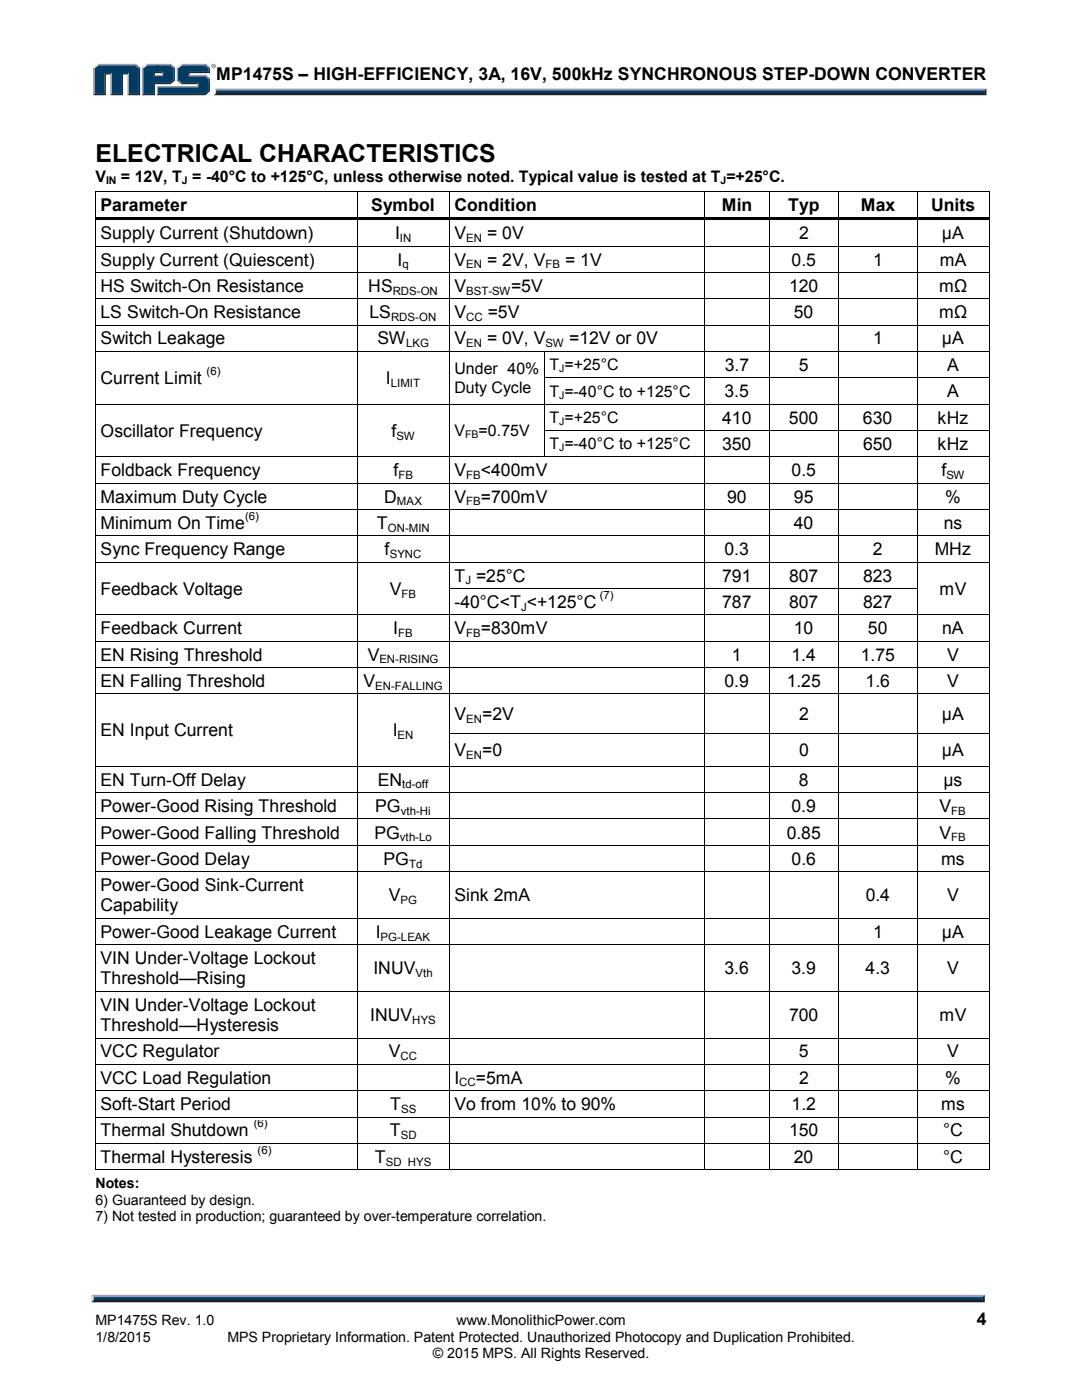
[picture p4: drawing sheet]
<svg xmlns="http://www.w3.org/2000/svg" width="216mm" height="279mm" viewBox="0 0 216 279" stroke-linecap="round" stroke-linejoin="round" font-family="sans-serif">
<defs><g id="words">
<text font-size="5" x="19" y="32.4">ELECTRICAL CHARACTERISTICS</text>
<g font-size="3.5">
<text x="43.1" y="15.9">MP1475S – HIGH-EFFICIENCY, 3A, 16V, 500kHz SYNCHRONOUS STEP-DOWN CONVERTER</text>
<text x="20.1" y="42.1">Parameter</text>
<text x="20.1" y="47.8">Supply Current (Shutdown)</text>
<text x="74.1" y="42.1">Symbol</text>
<text x="78.8" y="47.8">I</text>
<text x="90.7" y="42.1">Condition</text>
<text x="90.7" y="47.8">V</text>
<text x="97.2" y="47.8">= 0V</text>
<text x="144" y="42.1">Min</text>
<text x="157.3" y="42.1">Typ</text>
<text x="159.4" y="47.8">2</text>
<text x="171.8" y="42.1">Max</text>
<text x="185.8" y="42.1">Units</text>
<text x="188" y="47.8">μA</text>
<text x="20.1" y="53">Supply Current (Quiescent)</text>
<text x="79.3" y="53">I</text>
<text x="90.7" y="53">V</text>
<text x="97.2" y="53">= 2V, V</text>
<text x="112.8" y="53">= 1V</text>
<text x="158" y="53">0.5</text>
<text x="174.2" y="53">1</text>
<text x="187.5" y="53">mA</text>
<text x="20.1" y="58.3">HS Switch-On Resistance</text>
<text x="73.5" y="58.3">HS</text>
<text x="90.7" y="58.3">V</text>
<text x="102" y="58.3">=5V</text>
<text x="157.4" y="58.3">120</text>
<text x="187.4" y="58.3">mΩ</text>
<text x="20.1" y="63.5">LS Switch-On Resistance</text>
<text x="73.7" y="63.5">LS</text>
<text x="90.7" y="63.5">V</text>
<text x="97.3" y="63.5">=5V</text>
<text x="158.4" y="63.5">50</text>
<text x="187.4" y="63.5">mΩ</text>
<text x="20.1" y="68.7">Switch Leakage</text>
<text x="75.3" y="68.7">SW</text>
<text x="90.7" y="68.7">V</text>
<text x="97.2" y="68.7">= 0V, V</text>
<text x="113.6" y="68.7">=12V or 0V</text>
<text x="174.2" y="68.7">1</text>
<text x="188" y="68.7">μA</text>
<text x="20.1" y="76.7">Current Limit</text>
<text x="77" y="76.7">I</text>
<text x="144.6" y="74">3.7</text>
<text x="159.4" y="74">5</text>
<text x="189" y="74">A</text>
<text x="144.6" y="79.3">3.5</text>
<text x="189" y="79.3">A</text>
<text x="20.1" y="87.2">Oscillator Frequency</text>
<text x="78.1" y="87.2">f</text>
<text x="144.1" y="84.5">410</text>
<text x="144.1" y="89.8">350</text>
<text x="157.4" y="84.5">500</text>
<text x="172.2" y="84.5">630</text>
<text x="172.2" y="89.8">650</text>
<text x="187.1" y="84.5">kHz</text>
<text x="187.1" y="89.8">kHz</text>
<text x="20.1" y="95">Foldback Frequency</text>
<text x="78.5" y="95">f</text>
<text x="90.7" y="95">V</text>
<text x="95.9" y="95">&lt;400mV</text>
<text x="158" y="95">0.5</text>
<text x="187.8" y="95">f</text>
<text x="20.1" y="100.3">Maximum Duty Cycle</text>
<text x="76.7" y="100.3">D</text>
<text x="90.7" y="100.3">V</text>
<text x="95.9" y="100.3">=700mV</text>
<text x="145.1" y="100.3">90</text>
<text x="158.4" y="100.3">95</text>
<text x="188.6" y="100.3">%</text>
<text x="20.1" y="105.6">Minimum On Time</text>
<text x="75.2" y="105.6">T</text>
<text x="158.4" y="105.6">40</text>
<text x="188.3" y="105.6">ns</text>
<text x="20.1" y="110.8">Sync Frequency Range</text>
<text x="76.7" y="110.8">f</text>
<text x="144.6" y="110.8">0.3</text>
<text x="174.2" y="110.8">2</text>
<text x="186.5" y="110.8">MHz</text>
<text x="20.1" y="118.7">Feedback Voltage</text>
<text x="77.8" y="118.7">V</text>
<text x="90.7" y="116.1">T =25°C</text>
<text x="144.1" y="116.1">791</text>
<text x="157.4" y="116.1">807</text>
<text x="172.2" y="116.1">823</text>
<text x="187.5" y="118.7">mV</text>
<text x="90.7" y="121.3">-40°C&lt;T &lt;+125°C</text>
<text x="144.1" y="121.3">787</text>
<text x="157.4" y="121.3">807</text>
<text x="172.2" y="121.3">827</text>
<text x="20.1" y="126.6">Feedback Current</text>
<text x="20.1" y="131.8">EN Rising Threshold</text>
<text x="73.4" y="131.8">V</text>
<text x="78.5" y="126.6">I</text>
<text x="90.7" y="126.6">V</text>
<text x="95.9" y="126.6">=830mV</text>
<text x="146.1" y="131.8">1</text>
<text x="157.9" y="131.8">1.4</text>
<text x="158.4" y="126.6">10</text>
<text x="171.7" y="131.8">1.75</text>
<text x="173.2" y="126.6">50</text>
<text x="188" y="126.6">nA</text>
<text x="189" y="131.8">V</text>
<text x="20.1" y="137.1">EN Falling Threshold</text>
<text x="72.5" y="137.1">V</text>
<text x="144.6" y="137.1">0.9</text>
<text x="157" y="137.1">1.25</text>
<text x="172.7" y="137.1">1.6</text>
<text x="189" y="137.1">V</text>
<text x="90.7" y="143.7">V</text>
<text x="96.2" y="143.7">=2V</text>
<text x="159.4" y="143.7">2</text>
<text x="188" y="143.7">μA</text>
<text x="20.1" y="146.9">EN Input Current</text>
<text x="78.4" y="146.9">I</text>
<text x="90.7" y="150.9">V</text>
<text x="96.2" y="150.9">=0</text>
<text x="159.4" y="150.9">0</text>
<text x="188" y="150.9">μA</text>
<text x="20.1" y="156.8">EN Turn-Off Delay</text>
<text x="75.4" y="156.8">EN</text>
<text x="159.4" y="156.8">8</text>
<text x="188.3" y="156.8">μs</text>
<text x="20.1" y="162.1">Power-Good Rising Threshold</text>
<text x="20.1" y="167.3">Power-Good Falling Threshold</text>
<text x="74.7" y="167.3">PG</text>
<text x="74.9" y="162.1">PG</text>
<text x="157" y="167.3">0.85</text>
<text x="157.9" y="162.1">0.9</text>
<text x="187.5" y="167.3">V</text>
<text x="187.5" y="162.1">V</text>
<text x="20.1" y="172.6">Power-Good Delay</text>
<text x="76.5" y="172.6">PG</text>
<text x="157.9" y="172.6">0.6</text>
<text x="187.8" y="172.6">ms</text>
<text x="20.1" y="177.8">Power-Good Sink-Current</text>
<text x="77.6" y="179.9">V</text>
<text x="90.7" y="179.9">Sink 2mA</text>
<text x="172.7" y="179.9">0.4</text>
<text x="189" y="179.9">V</text>
<text x="20.1" y="181.9">Capability</text>
<text x="20.1" y="187.2">Power-Good Leakage Current</text>
<text x="75" y="187.2">I</text>
<text x="174.2" y="187.2">1</text>
<text x="188" y="187.2">μA</text>
<text x="20.1" y="192.4">VIN Under-Voltage Lockout</text>
<text x="20.1" y="196.5">Threshold—Rising</text>
<text x="74.5" y="194.4">INUV</text>
<text x="144.6" y="194.4">3.6</text>
<text x="157.9" y="194.4">3.9</text>
<text x="172.7" y="194.4">4.3</text>
<text x="189" y="194.4">V</text>
<text x="20.1" y="201.7">VIN Under-Voltage Lockout</text>
<text x="73.9" y="203.8">INUV</text>
<text x="157.4" y="203.8">700</text>
<text x="187.5" y="203.8">mV</text>
<text x="20.1" y="205.8">Threshold—Hysteresis</text>
<text x="20.1" y="211">VCC Regulator</text>
<text x="77.6" y="211">V</text>
<text x="159.4" y="211">5</text>
<text x="189" y="211">V</text>
<text x="20.1" y="216.3">VCC Load Regulation</text>
<text x="20.1" y="221.5">Soft-Start Period</text>
<text x="77.8" y="221.5">T</text>
<text x="90.7" y="216.3">I</text>
<text x="90.7" y="221.5">Vo from 10% to 90%</text>
<text x="95" y="216.3">=5mA</text>
<text x="158" y="221.5">1.2</text>
<text x="159.4" y="216.3">2</text>
<text x="187.8" y="221.5">ms</text>
<text x="188.6" y="216.3">%</text>
<text x="20.1" y="226.8">Thermal Shutdown</text>
<text x="77.8" y="226.8">T</text>
<text x="157.4" y="226.8">150</text>
<text x="188.2" y="226.8">°C</text>
<text x="20.1" y="232.1">Thermal Hysteresis</text>
<text x="74.8" y="232.1">T</text>
<text x="158.4" y="232.1">20</text>
<text x="188.2" y="232.1">°C</text>
<text x="194.9" y="264.5">4</text>
</g>
<g font-size="3.2">
<text x="19" y="36.4">V</text>
<text x="24.1" y="36.4">= 12V, T = -40°C to +125°C, unless otherwise noted. Typical value is tested at T =+25°C.</text>
<text x="90.7" y="74.7">Under 40%</text>
<text x="109.6" y="73.9">T =+25°C</text>
<text x="90.7" y="78.4">Duty Cycle</text>
<text x="109.6" y="79.2">T =-40°C to +125°C</text>
<text x="90.7" y="87.1">V</text>
<text x="95.5" y="87.1">=0.75V</text>
<text x="109.6" y="84.5">T =+25°C</text>
<text x="109.6" y="89.7">T =-40°C to +125°C</text>
</g>
<g font-size="2.8">
<text x="19" y="237.2">Notes:</text>
<text x="19" y="240.4">6) Guaranteed by design.</text>
<text x="19" y="243.7">7) Not tested in production; guaranteed by over-temperature correlation.</text>
<text x="19" y="267.9">1/8/2015</text>
<text x="19" y="264.5">MP1475S Rev. 1.0</text>
<text x="45.4" y="267.9">MPS Proprietary Information. Patent Protected. Unauthorized Photocopy and Duplication Prohibited.</text>
<text x="91.1" y="264.5">www.MonolithicPower.com</text>
<text x="86.4" y="271.1">© 2015 MPS. All Rights Reserved.</text>
</g>
<g font-size="2.3">
<text x="79.8" y="48.3">IN</text>
<text x="80.3" y="53.6">q</text>
<text x="93" y="48.3">EN</text>
<text x="93" y="53.6">EN</text>
<text x="108.8" y="53.6">FB</text>
<text x="78.4" y="58.8">RDS-ON</text>
<text x="93" y="58.8">BST-SW</text>
<text x="78" y="64.1">RDS-ON</text>
<text x="93" y="64.1">CC</text>
<text x="81" y="69.3">LKG</text>
<text x="93" y="69.3">EN</text>
<text x="108.8" y="69.3">SW</text>
<text x="41.2" y="74.9">(6)</text>
<text x="78" y="77.2">LIMIT</text>
<text x="79.1" y="87.7">SW</text>
<text x="79.5" y="95.6">FB</text>
<text x="93" y="95.6">FB</text>
<text x="188.8" y="95.6">SW</text>
<text x="79.2" y="100.8">MAX</text>
<text x="93" y="100.8">FB</text>
<text x="48.9" y="103.8">(6)</text>
<text x="77.4" y="106.1">ON-MIN</text>
<text x="77.8" y="111.4">SYNC</text>
<text x="80.1" y="119.3">FB</text>
<text x="92.9" y="116.6">J</text>
<text x="119.7" y="119.5">(7)</text>
<text x="104" y="121.9">J</text>
<text x="79.5" y="127.1">FB</text>
<text x="93" y="127.1">FB</text>
<text x="74.8" y="137.6">EN-FALLING</text>
<text x="75.7" y="132.4">EN-RISING</text>
<text x="79.3" y="147.5">EN</text>
<text x="93" y="144.2">EN</text>
<text x="93" y="151.4">EN</text>
<text x="80.3" y="157.4">td-off</text>
<text x="79.8" y="167.9">vth-Lo</text>
<text x="80" y="162.6">vth-Hi</text>
<text x="189.8" y="162.6">FB</text>
<text x="189.8" y="167.9">FB</text>
<text x="81.6" y="173.1">Td</text>
<text x="79.9" y="180.4">PG</text>
<text x="75.9" y="187.7">PG-LEAK</text>
<text x="82.9" y="195">Vth</text>
<text x="82.3" y="204.3">HYS</text>
<text x="79.9" y="211.6">CC</text>
<text x="91.7" y="216.8">CC</text>
<text x="50.6" y="225">(6)</text>
<text x="80" y="227.3">SD</text>
<text x="80.1" y="222.1">SS</text>
<text x="51.4" y="230.3">(6)</text>
<text x="77" y="232.6">SD HYS</text>
</g>
<g font-size="2.1">
<text x="21.2" y="36.7">IN</text>
<text x="36.3" y="36.7">J</text>
<text x="143.8" y="36.7">J</text>
<text x="111.5" y="74.3">J</text>
<text x="111.5" y="79.5">J</text>
<text x="92.8" y="87.4">FB</text>
<text x="111.5" y="84.8">J</text>
<text x="111.5" y="90">J</text>
</g>
</g></defs>
<path d="M18.7 259.2h177.4l.4 .7h-178.3z" fill="#231f20"/>
<path d="M18.3 258.4h178.2l-.4 .8h-177.4z" fill="#94a0b9"/>
<path d="M196.5 258.4v1.5l-.4-.4v-.6z" fill="#001339"/>
<path d="M18.7 258.9h177.4v.6h-177.4z" fill="#003b63"/>
<path d="M18.2 258.4l.5 .5v.5l-.5 .5z" fill="#dcddde"/>
<path d="M42.9 17.7h153.9l-.4 .7h-153.3z" fill="#94a0b9"/>
<path d="M43.1 18.4h153.3l.4 .6h-154.3l.4-.2z" fill="#231f20"/>
<path d="M196.4 18.1l.4-.4v1.3l-.4-.4z" fill="#001339"/>
<path d="M43.1 18.1h153.3v.5h-153.4z" fill="#003b63"/>
<path d="M42.9 17.7l.2 .5a.79 .79 0 0 1-.6 .8l.1-.1a1.23 1.23 0 0 0 .3-1.2z" fill="#dcddde"/>
<path d="M30.7 15.2l.2-.3h1.4l.3 .3z" fill="#94a0b9"/>
<g fill="#003b63">
<path d="M18.9 13.6l.8-.6h7.2l.8 .6v5.1h-2v-4.1h-1.4v4.1h-2v-4.1h-1.5v4.1h-1.9z"/>
<path d="M28.6 13.6l.8-.6h2.2v1.3h-.9v.9h1.9v-.9h-1.3v-1.3h2.5l.8 .6v2.3l-.8 .6h-3.1v2.2h-2.1z"/>
<path d="M31.5 17.4h8v-.9h-3.2l-.8-.6v-2.3l.8-.6h4.5l.8 .6v.7h-4v.9h3.2l.8 .6v2.2l-.8 .7h-9.3z"/>
</g>
<path d="M36.2 12.9h4.8" fill="none" stroke="#94a0b9" stroke-width=".26"/>
<path d="M35.3 13.4l.9-.7 .1 .3-.8 .6z" fill="#dcddde"/>
<path d="M35.4 13.4v2.7" fill="none" stroke="#94a0b9" stroke-width=".27"/>
<path d="M35.3 16.1l.2-.2 .8 .6-.1 .3z" fill="#547194"/>
<path d="M36.2 16.7h3.4" fill="none" stroke="#001339" stroke-width=".26"/>
<g fill="#94a0b9">
<path d="M31.3 17.2h8v-.4l.3-.3v.9h-8z"/>
<path d="M31.3 17.2l.3 .2v1.3l-.3 .3z"/>
</g>
<path d="M37.6 14.3h4v-.7l.3-.2v1.2h-4.1v.3l-.2 .3z" fill="#001339"/>
<path d="M37.6 15.1h3.4" fill="none" stroke="#94a0b9" stroke-width=".26"/>
<path d="M41 14.9l.9 .8-.3 .1-.8-.6z" fill="#547194"/>
<g fill="#001339">
<path d="M31.3 19l.3-.3h9.2l.8-.7v-2.2l.3-.1v2.5l-.9 .8z"/>
<path d="M30.7 16.5h3.1l.8-.6v-2.3l.3-.2v2.7l-.9 .7h-3.1v2.2h-2.6l.3-.3h2.1z"/>
</g>
<path d="M34 12.7l.9 .7-.3 .2-.8-.6z" fill="#547194"/>
<path d="M29.2 12.9h4.8" fill="none" stroke="#94a0b9" stroke-width=".26"/>
<path d="M28.3 13.4l.9-.7 .2 .3-.8 .6z" fill="#dcddde"/>
<path d="M28.5 13.4v5.6" fill="none" stroke="#94a0b9" stroke-width=".27"/>
<path d="M32.3 14.6l.3-.3v.9l-.3-.3z" fill="#94a0b9"/>
<g fill="#001339">
<path d="M30.7 14.3h1.9l-.3 .3h-1.4v.3l-.2 .3z"/>
<path d="M27.7 13.6l.3-.2v5.6h-2.6l.3-.3h2z"/>
</g>
<path d="M27.1 12.7l.9 .7-.3 .2-.8-.6z" fill="#547194"/>
<path d="M19.5 12.9h7.6" fill="none" stroke="#94a0b9" stroke-width=".26"/>
<path d="M18.6 13.4l.9-.7 .2 .3-.8 .6z" fill="#dcddde"/>
<path d="M18.7 13.4v5.6" fill="none" stroke="#94a0b9" stroke-width=".27"/>
<path d="M20.8 14.6h1.5l-.3 .3h-.9v4.1h-2.5l.3-.3h1.9z" fill="#001339"/>
<path d="M22.1 14.6v4.4" fill="none" stroke="#94a0b9" stroke-width=".27"/>
<path d="M24.3 14.6h1.4l-.3 .3h-.9v4.1h-2.5l.3-.3h2z" fill="#001339"/>
<path d="M25.6 14.6v4.4" fill="none" stroke="#94a0b9" stroke-width=".27"/>
<path d="M41 12.7l.9 .7-.3 .2-.8-.6z" fill="#547194"/>
<path d="M42.2 13.2a.45 .45 0 0 1 .9 0 .45 .45 0 0 1-.9 0zM42.3 13.2a.37 .37 0 0 0 .7 0 .37 .37 0 0 0-.7 0zM42.5 12.9l.3 .1v.4l-.2-.2-.1 .2zM42.5 13v.2l.2-.1z" fill="#231f20"/>
<g fill="#000">
<path d="M19 38.2h.1v.7h-.1zM71.2 38.2h.2v.7h-.2zM89.6 38.2h.1v.7h-.1zM140.5 38.2h.2v.7h-.2zM153.4 38.2h.2v.7h-.2zM167.3 38.2h.1v.7h-.1zM182.9 38.2h.2v.7h-.2zM197.3 38.2h.1v.7h-.1zM197.3 38.2h.1v.2h-.1zM19 43.4h.1v1.1h-.1zM19 49.1h.1v.6h-.1zM19 54.3h.1v.7h-.1z"/>
<path d="M19.1 43.4h52.1v.5h-52.1zM71.2 43.9h.2v.6h-.2zM71.2 43.4h18.4v.5h-18.4zM71.2 49.1h.2v.6h-.2zM71.2 54.3h.2v.7h-.2zM89.6 43.9h.1v.6h-.1zM89.6 43.4h50.9v.5h-50.9zM89.6 49.1h.1v.6h-.1zM89.6 54.3h.1v.7h-.1zM140.5 43.9h.2v.6h-.2zM140.5 43.4h12.9v.5h-12.9zM140.5 49.1h.2v.6h-.2z"/>
<path d="M140.5 54.3h.2v.7h-.2zM153.4 43.9h.2v.6h-.2zM153.4 43.4h13.9v.5h-13.9zM153.4 49.1h.2v.6h-.2zM153.4 54.3h.2v.7h-.2zM167.3 43.9h.1v.6h-.1zM167.3 43.4h15.6v.5h-15.6zM167.3 49.1h.1v.6h-.1zM167.3 54.3h.1v.7h-.1zM182.9 43.9h.2v.6h-.2zM182.9 43.4h14.4v.5h-14.4zM182.9 49.1h.2v.6h-.2z"/>
<path d="M182.9 54.3h.2v.7h-.2zM197.3 43.4h.1v1.1h-.1zM197.3 49.1h.1v.6h-.1zM197.3 54.3h.1v.7h-.1zM19 59.6h.1v.6h-.1zM19 64.8h.1v.7h-.1zM19 70.1h.1v.6h-.1zM19 75.3h.1v.7h-.1zM71.2 59.6h.2v.6h-.2zM71.2 64.8h.2v.7h-.2zM71.2 70.1h.2v.6h-.2zM71.2 75.3h.2v.7h-.2z"/>
<path d="M89.6 59.6h.1v.6h-.1zM89.6 64.8h.1v.7h-.1zM89.6 70.1h.1v.6h-.1zM89.6 75.3h.1v.7h-.1zM108.5 70.1h.2v.6h-.2zM108.5 75.3h.2v.7h-.2zM140.5 59.6h.2v.6h-.2zM140.5 64.8h.2v.7h-.2zM140.5 70.1h.2v.6h-.2zM140.5 75.3h.2v.7h-.2zM153.4 59.6h.2v.6h-.2zM153.4 64.8h.2v.7h-.2z"/>
<path d="M153.4 70.1h.2v.6h-.2zM153.4 75.3h.2v.7h-.2zM167.3 59.6h.1v.6h-.1zM167.3 64.8h.1v.7h-.1zM167.3 70.1h.1v.6h-.1zM167.3 75.3h.1v.7h-.1zM182.9 59.6h.2v.6h-.2zM182.9 64.8h.2v.7h-.2zM182.9 70.1h.2v.6h-.2zM182.9 75.3h.2v.7h-.2zM197.3 59.6h.1v.6h-.1zM197.3 64.8h.1v.7h-.1z"/>
<path d="M197.3 70.1h.1v.6h-.1zM197.3 75.3h.1v.7h-.1zM19 80.6h.1v.7h-.1zM19 85.9h.1v.6h-.1zM19 91.1h.1v.7h-.1zM19 96.4h.1v.6h-.1zM71.2 80.6h.2v.7h-.2zM71.2 85.9h.2v.6h-.2zM71.2 91.1h.2v.7h-.2zM71.2 96.4h.2v.6h-.2zM89.6 80.6h.1v.7h-.1zM89.6 85.9h.1v.6h-.1z"/>
<path d="M89.6 91.1h.1v.7h-.1zM89.6 96.4h.1v.6h-.1zM108.5 80.6h.2v.7h-.2zM108.5 85.9h.2v.6h-.2zM140.5 80.6h.2v.7h-.2zM140.5 85.9h.2v.6h-.2zM140.5 91.1h.2v.7h-.2zM140.5 96.4h.2v.6h-.2zM153.4 80.6h.2v.7h-.2zM153.4 85.9h.2v.6h-.2zM153.4 91.1h.2v.7h-.2zM153.4 96.4h.2v.6h-.2z"/>
<path d="M167.3 80.6h.1v.7h-.1zM167.3 85.9h.1v.6h-.1zM167.3 91.1h.1v.7h-.1zM167.3 96.4h.1v.6h-.1zM182.9 80.6h.2v.7h-.2zM182.9 85.9h.2v.6h-.2zM182.9 91.1h.2v.7h-.2zM182.9 96.4h.2v.6h-.2zM197.3 80.6h.1v.7h-.1zM197.3 85.9h.1v.6h-.1zM197.3 91.1h.1v.7h-.1zM197.3 96.4h.1v.6h-.1z"/>
<path d="M19 101.6h.1v.7h-.1zM19 106.8h.1v.7h-.1zM19 112.1h.1v.7h-.1zM19 117.4h.1v.7h-.1zM71.2 101.6h.2v.7h-.2zM71.2 106.8h.2v.7h-.2zM71.2 112.1h.2v.7h-.2zM71.2 117.4h.2v.7h-.2zM89.6 101.6h.1v.7h-.1zM89.6 106.8h.1v.7h-.1zM89.6 112.1h.1v.7h-.1zM89.6 117.4h.1v.7h-.1z"/>
<path d="M140.5 101.6h.2v.7h-.2zM140.5 106.8h.2v.7h-.2zM140.5 112.1h.2v.7h-.2zM140.5 117.4h.2v.7h-.2zM153.4 101.6h.2v.7h-.2zM153.4 106.8h.2v.7h-.2zM153.4 112.1h.2v.7h-.2zM153.4 117.4h.2v.7h-.2zM167.3 101.6h.1v.7h-.1zM167.3 106.8h.1v.7h-.1zM167.3 112.1h.1v.7h-.1zM167.3 117.4h.1v.7h-.1z"/>
<path d="M182.9 101.6h.2v.7h-.2zM182.9 106.8h.2v.7h-.2zM182.9 112.1h.2v.7h-.2zM182.9 117.4h.2v.7h-.2zM197.3 101.6h.1v.7h-.1zM197.3 106.8h.1v.7h-.1zM197.3 112.1h.1v.7h-.1zM197.3 117.4h.1v.7h-.1zM19 122.6h.1v.7h-.1zM19 127.9h.1v.7h-.1zM19 133.1h.1v.7h-.1zM19 138.4h.1v.7h-.1z"/>
<path d="M71.2 122.6h.2v.7h-.2zM71.2 127.9h.2v.7h-.2zM71.2 133.1h.2v.7h-.2zM71.2 138.4h.2v.7h-.2zM89.6 122.6h.1v.7h-.1zM89.6 127.9h.1v.7h-.1zM89.6 133.1h.1v.7h-.1zM89.6 138.4h.1v.7h-.1zM140.5 122.6h.2v.7h-.2zM140.5 127.9h.2v.7h-.2zM140.5 133.1h.2v.7h-.2zM140.5 138.4h.2v.7h-.2z"/>
<path d="M153.4 122.6h.2v.7h-.2zM153.4 127.9h.2v.7h-.2zM153.4 133.1h.2v.7h-.2zM153.4 138.4h.2v.7h-.2zM167.3 122.6h.1v.7h-.1zM167.3 127.9h.1v.7h-.1zM167.3 133.1h.1v.7h-.1zM167.3 138.4h.1v.7h-.1zM182.9 122.6h.2v.7h-.2zM182.9 127.9h.2v.7h-.2zM182.9 133.1h.2v.7h-.2zM182.9 138.4h.2v.7h-.2z"/>
<path d="M197.3 122.6h.1v.7h-.1zM197.3 127.9h.1v.7h-.1zM197.3 133.1h.1v.7h-.1zM197.3 138.4h.1v.7h-.1zM19 146.3h.1v.7h-.1zM19 152.9h.1v.6h-.1zM19 158.1h.1v.7h-.1zM71.2 146.3h.2v.7h-.2zM71.2 152.9h.2v.6h-.2zM71.2 158.1h.2v.7h-.2zM89.6 146.3h.1v.7h-.1zM89.6 152.9h.1v.6h-.1z"/>
<path d="M89.6 158.1h.1v.7h-.1zM140.5 146.3h.2v.7h-.2zM140.5 152.9h.2v.6h-.2zM140.5 158.1h.2v.7h-.2zM153.4 146.3h.2v.7h-.2zM153.4 152.9h.2v.6h-.2zM153.4 158.1h.2v.7h-.2zM167.3 146.3h.1v.7h-.1zM167.3 152.9h.1v.6h-.1zM167.3 158.1h.1v.7h-.1zM182.9 146.3h.2v.7h-.2zM182.9 152.9h.2v.6h-.2z"/>
<path d="M182.9 158.1h.2v.7h-.2zM197.3 146.3h.1v.7h-.1zM197.3 152.9h.1v.6h-.1zM197.3 158.1h.1v.7h-.1zM19 163.4h.1v.6h-.1zM19 168.7h.1v.6h-.1zM19 173.9h.1v.7h-.1zM71.2 163.4h.2v.6h-.2zM71.2 168.7h.2v.6h-.2zM71.2 173.9h.2v.7h-.2zM89.6 163.4h.1v.6h-.1zM89.6 168.7h.1v.6h-.1z"/>
<path d="M89.6 173.9h.1v.7h-.1zM140.5 163.4h.2v.6h-.2zM140.5 168.7h.2v.6h-.2zM140.5 173.9h.2v.7h-.2zM153.4 163.4h.2v.6h-.2zM153.4 168.7h.2v.6h-.2zM153.4 173.9h.2v.7h-.2zM167.3 163.4h.1v.6h-.1zM167.3 168.7h.1v.6h-.1zM167.3 173.9h.1v.7h-.1zM182.9 163.4h.2v.6h-.2zM182.9 168.7h.2v.6h-.2z"/>
<path d="M182.9 173.9h.2v.7h-.2zM197.3 163.4h.1v.6h-.1zM197.3 168.7h.1v.6h-.1zM197.3 173.9h.1v.7h-.1zM19 183.2h.1v.7h-.1zM19 188.5h.1v.6h-.1zM19 197.8h.1v.7h-.1zM71.2 183.2h.2v.7h-.2zM71.2 188.5h.2v.6h-.2zM71.2 197.8h.2v.7h-.2zM89.6 183.2h.1v.7h-.1zM89.6 188.5h.1v.6h-.1z"/>
<path d="M89.6 197.8h.1v.7h-.1zM140.5 183.2h.2v.7h-.2zM140.5 188.5h.2v.6h-.2zM140.5 197.8h.2v.7h-.2zM153.4 183.2h.2v.7h-.2zM153.4 188.5h.2v.6h-.2zM153.4 197.8h.2v.7h-.2zM167.3 183.2h.1v.7h-.1zM167.3 188.5h.1v.6h-.1zM167.3 197.8h.1v.7h-.1zM182.9 183.2h.2v.7h-.2zM182.9 188.5h.2v.6h-.2z"/>
<path d="M182.9 197.8h.2v.7h-.2zM197.3 183.2h.1v.7h-.1zM197.3 188.5h.1v.6h-.1zM197.3 197.8h.1v.7h-.1zM19 207.1h.1v.7h-.1zM19 212.3h.1v.7h-.1zM19 217.6h.1v.7h-.1zM71.2 207.1h.2v.7h-.2zM71.2 212.3h.2v.7h-.2zM71.2 217.6h.2v.7h-.2zM89.6 207.1h.1v.7h-.1zM89.6 212.3h.1v.7h-.1z"/>
<path d="M89.6 217.6h.1v.7h-.1zM140.5 207.1h.2v.7h-.2zM140.5 212.3h.2v.7h-.2zM140.5 217.6h.2v.7h-.2zM153.4 207.1h.2v.7h-.2zM153.4 212.3h.2v.7h-.2zM153.4 217.6h.2v.7h-.2zM167.3 207.1h.1v.7h-.1zM167.3 212.3h.1v.7h-.1zM167.3 217.6h.1v.7h-.1zM182.9 207.1h.2v.7h-.2zM182.9 212.3h.2v.7h-.2z"/>
<path d="M182.9 217.6h.2v.7h-.2zM197.3 207.1h.1v.7h-.1zM197.3 212.3h.1v.7h-.1zM197.3 217.6h.1v.7h-.1zM19 222.8h.1v.7h-.1zM19 228.1h.1v.7h-.1zM71.2 222.8h.2v.7h-.2zM71.2 228.1h.2v.7h-.2zM89.6 222.8h.1v.7h-.1zM89.6 228.1h.1v.7h-.1zM140.5 222.8h.2v.7h-.2zM140.5 228.1h.2v.7h-.2z"/>
<path d="M153.4 222.8h.2v.7h-.2zM153.4 228.1h.2v.7h-.2zM167.3 222.8h.1v.7h-.1zM167.3 228.1h.1v.7h-.1zM182.9 222.8h.2v.7h-.2zM182.9 228.1h.2v.7h-.2zM197.3 222.8h.1v.7h-.1zM197.3 228.1h.1v.7h-.1zM197.3 233.4h.1v.2h-.1z"/>
</g>
<g fill="none" stroke="#000" stroke-width=".2">
<path d="M19 38.3h52.2M19 38.9v4.5M71.3 38.9v4.5M71.4 38.3h18.2M89.7 38.9v4.5M89.7 38.3h50.8M140.6 38.9v4.5M140.7 38.3h12.7M153.5 38.9v4.5M153.6 38.3h13.7M167.3 38.9v4.5M167.4 38.3h15.5"/>
<path d="M183 38.9v4.5M183.1 38.3h14.2M197.4 38.9v4.5M19 44.5v4.6M19 49.7v4.6M19 55v4.6M19.1 49.1h52.1M19.1 54.4h52.1M19.1 59.6h52.1M71.3 44.5v4.6M71.3 49.7v4.6M71.3 55v4.6"/>
<path d="M71.4 49.1h18.2M71.4 54.4h18.2M71.4 59.6h18.2M89.7 44.5v4.6M89.7 49.7v4.6M89.7 55v4.6M89.7 49.1h50.8M89.7 54.4h50.8M89.7 59.6h50.8M140.6 44.5v4.6M140.6 49.7v4.6M140.6 55v4.6"/>
<path d="M140.7 49.1h12.7M140.7 54.4h12.7M140.7 59.6h12.7M153.5 44.5v4.6M153.5 49.7v4.6M153.5 55v4.6M153.6 49.1h13.7M153.6 54.4h13.7M153.6 59.6h13.7M167.3 44.5v4.6M167.3 49.7v4.6M167.3 55v4.6"/>
<path d="M167.4 49.1h15.5M167.4 54.4h15.5M167.4 59.6h15.5M183 44.5v4.6M183 49.7v4.6M183 55v4.6M183.1 49.1h14.2M183.1 54.4h14.2M183.1 59.6h14.2M197.4 44.5v4.6M197.4 49.7v4.6M197.4 55v4.6"/>
<path d="M19 60.2v4.6M19 65.5v4.6M19 70.7v4.6M19 76v4.6M19.1 64.9h52.1M19.1 70.1h52.1M71.3 60.2v4.6M71.3 65.5v4.6M71.3 70.7v4.6M71.3 76v4.6M71.4 64.9h18.2M71.4 70.1h18.2"/>
<path d="M89.7 60.2v4.6M89.7 65.5v4.6M89.7 70.7v4.6M89.7 76v4.6M89.7 64.9h50.8M89.7 70.1h18.8M108.6 70.7v4.6M108.6 76v4.6M108.7 70.1h31.8M108.7 75.4h31.8M140.6 60.2v4.6M140.6 65.5v4.6"/>
<path d="M140.6 70.7v4.6M140.6 76v4.6M140.7 64.9h12.7M140.7 70.1h12.7M140.7 75.4h12.7M153.5 60.2v4.6M153.5 65.5v4.6M153.5 70.7v4.6M153.5 76v4.6M153.6 64.9h13.7M153.6 70.1h13.7M153.6 75.4h13.7"/>
<path d="M167.3 60.2v4.6M167.3 65.5v4.6M167.3 70.7v4.6M167.3 76v4.6M167.4 64.9h15.5M167.4 70.1h15.5M167.4 75.4h15.5M183 60.2v4.6M183 65.5v4.6M183 70.7v4.6M183 76v4.6M183.1 64.9h14.2"/>
<path d="M183.1 70.1h14.2M183.1 75.4h14.2M197.4 60.2v4.6M197.4 65.5v4.6M197.4 70.7v4.6M197.4 76v4.6M19 81.3v4.6M19 86.5v4.6M19 91.8v4.6M19 97v4.6M19.1 80.7h52.1M19.1 91.2h52.1"/>
<path d="M19.1 96.4h52.1M71.3 81.3v4.6M71.3 86.5v4.6M71.3 91.8v4.6M71.3 97v4.6M71.4 80.7h18.2M71.4 91.2h18.2M71.4 96.4h18.2M89.7 81.3v4.6M89.7 86.5v4.6M89.7 91.8v4.6M89.7 97v4.6"/>
<path d="M89.7 80.7h18.8M89.7 91.2h50.8M89.7 96.4h50.8M108.6 81.3v4.6M108.6 86.5v4.6M108.7 80.7h31.8M108.7 85.9h31.8M140.6 81.3v4.6M140.6 86.5v4.6M140.6 91.8v4.6M140.6 97v4.6M140.7 80.7h12.7"/>
<path d="M140.7 85.9h12.7M140.7 91.2h12.7M140.7 96.4h12.7M153.5 81.3v4.6M153.5 86.5v4.6M153.5 91.8v4.6M153.5 97v4.6M153.6 80.7h13.7M153.6 85.9h13.7M153.6 91.2h13.7M153.6 96.4h13.7M167.3 81.3v4.6"/>
<path d="M167.3 86.5v4.6M167.3 91.8v4.6M167.3 97v4.6M167.4 80.7h15.5M167.4 85.9h15.5M167.4 91.2h15.5M167.4 96.4h15.5M183 81.3v4.6M183 86.5v4.6M183 91.8v4.6M183 97v4.6M183.1 80.7h14.2"/>
<path d="M183.1 85.9h14.2M183.1 91.2h14.2M183.1 96.4h14.2M197.4 81.3v4.6M197.4 86.5v4.6M197.4 91.8v4.6M197.4 97v4.6M19 102.3v4.5M19 107.5v4.6M19 112.8v4.6M19 118.1v4.5M19.1 101.7h52.1"/>
<path d="M19.1 106.9h52.1M19.1 112.2h52.1M71.3 102.3v4.5M71.3 107.5v4.6M71.3 112.8v4.6M71.3 118.1v4.5M71.4 101.7h18.2M71.4 106.9h18.2M71.4 112.2h18.2M89.7 102.3v4.5M89.7 107.5v4.6M89.7 112.8v4.6"/>
<path d="M89.7 118.1v4.5M89.7 101.7h50.8M89.7 106.9h50.8M89.7 112.2h50.8M89.7 117.5h50.8M140.6 102.3v4.5M140.6 107.5v4.6M140.6 112.8v4.6M140.6 118.1v4.5M140.7 101.7h12.7M140.7 106.9h12.7M140.7 112.2h12.7"/>
<path d="M140.7 117.5h12.7M153.5 102.3v4.5M153.5 107.5v4.6M153.5 112.8v4.6M153.5 118.1v4.5M153.6 101.7h13.7M153.6 106.9h13.7M153.6 112.2h13.7M153.6 117.5h13.7M167.3 102.3v4.5M167.3 107.5v4.6M167.3 112.8v4.6"/>
<path d="M167.3 118.1v4.5M167.4 101.7h15.5M167.4 106.9h15.5M167.4 112.2h15.5M167.4 117.5h15.5M183 102.3v4.5M183 107.5v4.6M183 112.8v4.6M183 118.1v4.5M183.1 101.7h14.2M183.1 106.9h14.2M183.1 112.2h14.2"/>
<path d="M197.4 102.3v4.5M197.4 107.5v4.6M197.4 112.8v4.6M197.4 118.1v4.5M19 123.3v4.6M19 128.6v4.5M19 133.8v4.6M19 139.1v7.2M19.1 122.7h52.1M19.1 128h52.1M19.1 133.2h52.1M19.1 138.5h52.1"/>
<path d="M71.3 123.3v4.6M71.3 128.6v4.5M71.3 133.8v4.6M71.3 139.1v7.2M71.4 122.7h18.2M71.4 128h18.2M71.4 133.2h18.2M71.4 138.5h18.2M89.7 123.3v4.6M89.7 128.6v4.5M89.7 133.8v4.6M89.7 139.1v7.2"/>
<path d="M89.7 122.7h50.8M89.7 128h50.8M89.7 133.2h50.8M89.7 138.5h50.8M140.6 123.3v4.6M140.6 128.6v4.5M140.6 133.8v4.6M140.6 139.1v7.2M140.7 122.7h12.7M140.7 128h12.7M140.7 133.2h12.7M140.7 138.5h12.7"/>
<path d="M153.5 123.3v4.6M153.5 128.6v4.5M153.5 133.8v4.6M153.5 139.1v7.2M153.6 122.7h13.7M153.6 128h13.7M153.6 133.2h13.7M153.6 138.5h13.7M167.3 123.3v4.6M167.3 128.6v4.5M167.3 133.8v4.6M167.3 139.1v7.2"/>
<path d="M167.4 122.7h15.5M167.4 128h15.5M167.4 133.2h15.5M167.4 138.5h15.5M183 123.3v4.6M183 128.6v4.5M183 133.8v4.6M183 139.1v7.2M183.1 122.7h14.2M183.1 128h14.2M183.1 133.2h14.2M183.1 138.5h14.2"/>
<path d="M197.4 123.3v4.6M197.4 128.6v4.5M197.4 133.8v4.6M197.4 139.1v7.2M19 147v5.9M19 153.5v4.6M19 158.8v4.6M19.1 153h52.1M19.1 158.2h52.1M71.3 147v5.9M71.3 153.5v4.6M71.3 158.8v4.6"/>
<path d="M71.4 153h18.2M71.4 158.2h18.2M89.7 147v5.9M89.7 153.5v4.6M89.7 158.8v4.6M89.7 146.4h50.8M89.7 153h50.8M89.7 158.2h50.8M140.6 147v5.9M140.6 153.5v4.6M140.6 158.8v4.6M140.7 146.4h12.7"/>
<path d="M140.7 153h12.7M140.7 158.2h12.7M153.5 147v5.9M153.5 153.5v4.6M153.5 158.8v4.6M153.6 146.4h13.7M153.6 153h13.7M153.6 158.2h13.7M167.3 147v5.9M167.3 153.5v4.6M167.3 158.8v4.6M167.4 146.4h15.5"/>
<path d="M167.4 153h15.5M167.4 158.2h15.5M183 147v5.9M183 153.5v4.6M183 158.8v4.6M183.1 146.4h14.2M183.1 153h14.2M183.1 158.2h14.2M197.4 147v5.9M197.4 153.5v4.6M197.4 158.8v4.6M19 164v4.7"/>
<path d="M19 169.3v4.6M19 174.6v8.6M19.1 163.4h52.1M19.1 168.7h52.1M19.1 174h52.1M71.3 164v4.7M71.3 169.3v4.6M71.3 174.6v8.6M71.4 163.4h18.2M71.4 168.7h18.2M71.4 174h18.2M89.7 164v4.7"/>
<path d="M89.7 169.3v4.6M89.7 174.6v8.6M89.7 163.4h50.8M89.7 168.7h50.8M89.7 174h50.8M140.6 164v4.7M140.6 169.3v4.6M140.6 174.6v8.6M140.7 163.4h12.7M140.7 168.7h12.7M140.7 174h12.7M153.5 164v4.7"/>
<path d="M153.5 169.3v4.6M153.5 174.6v8.6M153.6 163.4h13.7M153.6 168.7h13.7M153.6 174h13.7M167.3 164v4.7M167.3 169.3v4.6M167.3 174.6v8.6M167.4 163.4h15.5M167.4 168.7h15.5M167.4 174h15.5M183 164v4.7"/>
<path d="M183 169.3v4.6M183 174.6v8.6M183.1 163.4h14.2M183.1 168.7h14.2M183.1 174h14.2M197.4 164v4.7M197.4 169.3v4.6M197.4 174.6v8.6M19 183.9v4.6M19 189.1v8.7M19 198.5v8.6M19.1 183.3h52.1"/>
<path d="M19.1 188.6h52.1M19.1 197.9h52.1M71.3 183.9v4.6M71.3 189.1v8.7M71.3 198.5v8.6M71.4 183.3h18.2M71.4 188.6h18.2M71.4 197.9h18.2M89.7 183.9v4.6M89.7 189.1v8.7M89.7 198.5v8.6M89.7 183.3h50.8"/>
<path d="M89.7 188.6h50.8M89.7 197.9h50.8M140.6 183.9v4.6M140.6 189.1v8.7M140.6 198.5v8.6M140.7 183.3h12.7M140.7 188.6h12.7M140.7 197.9h12.7M153.5 183.9v4.6M153.5 189.1v8.7M153.5 198.5v8.6M153.6 183.3h13.7"/>
<path d="M153.6 188.6h13.7M153.6 197.9h13.7M167.3 183.9v4.6M167.3 189.1v8.7M167.3 198.5v8.6M167.4 183.3h15.5M167.4 188.6h15.5M167.4 197.9h15.5M183 183.9v4.6M183 189.1v8.7M183 198.5v8.6M183.1 183.3h14.2"/>
<path d="M183.1 188.6h14.2M183.1 197.9h14.2M197.4 183.9v4.6M197.4 189.1v8.7M197.4 198.5v8.6M19 207.8v4.5M19 213v4.6M19 218.3v4.5M19.1 207.2h52.1M19.1 212.4h52.1M19.1 217.7h52.1M71.3 207.8v4.5"/>
<path d="M71.3 213v4.6M71.3 218.3v4.5M71.4 207.2h18.2M71.4 212.4h18.2M71.4 217.7h18.2M89.7 207.8v4.5M89.7 213v4.6M89.7 218.3v4.5M89.7 207.2h50.8M89.7 212.4h50.8M89.7 217.7h50.8M140.6 207.8v4.5"/>
<path d="M140.6 213v4.6M140.6 218.3v4.5M140.7 207.2h12.7M140.7 212.4h12.7M140.7 217.7h12.7M153.5 207.8v4.5M153.5 213v4.6M153.5 218.3v4.5M153.6 207.2h13.7M153.6 212.4h13.7M153.6 217.7h13.7M167.3 207.8v4.5"/>
<path d="M167.3 213v4.6M167.3 218.3v4.5M167.4 207.2h15.5M167.4 212.4h15.5M167.4 217.7h15.5M183 207.8v4.5M183 213v4.6M183 218.3v4.5M183.1 207.2h14.2M183.1 212.4h14.2M183.1 217.7h14.2M197.4 207.8v4.5"/>
<path d="M197.4 213v4.6M197.4 218.3v4.5M19 233.5h52.2M19 223.5v4.6M19 228.8v4.8M19.1 222.9h52.1M19.1 228.2h52.1M71.3 223.5v4.6M71.3 228.8v4.8M71.4 222.9h18.2M71.4 228.2h18.2M71.4 233.5h18.2"/>
<path d="M89.7 223.5v4.6M89.7 228.8v4.8M89.7 222.9h50.8M89.7 228.2h50.8M89.7 233.5h50.8M140.6 223.5v4.6M140.6 228.8v4.8M140.7 222.9h12.7M140.7 228.2h12.7M140.7 233.5h12.7M153.5 223.5v4.6M153.5 228.8v4.8"/>
<path d="M153.6 222.9h13.7M153.6 228.2h13.7M153.6 233.5h13.7M167.3 223.5v4.6M167.3 228.8v4.8M167.4 222.9h15.5M167.4 228.2h15.5M167.4 233.5h15.5M183 223.5v4.6M183 228.8v4.8M183.1 222.9h14.2M183.1 228.2h14.2"/>
<path d="M183.1 233.5h14.2M197.4 223.5v4.6M197.4 228.8v4.8"/>
</g>
<use href="#words"/>
</svg>
